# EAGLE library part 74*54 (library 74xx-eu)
4-wide AND OR INVERTER gates

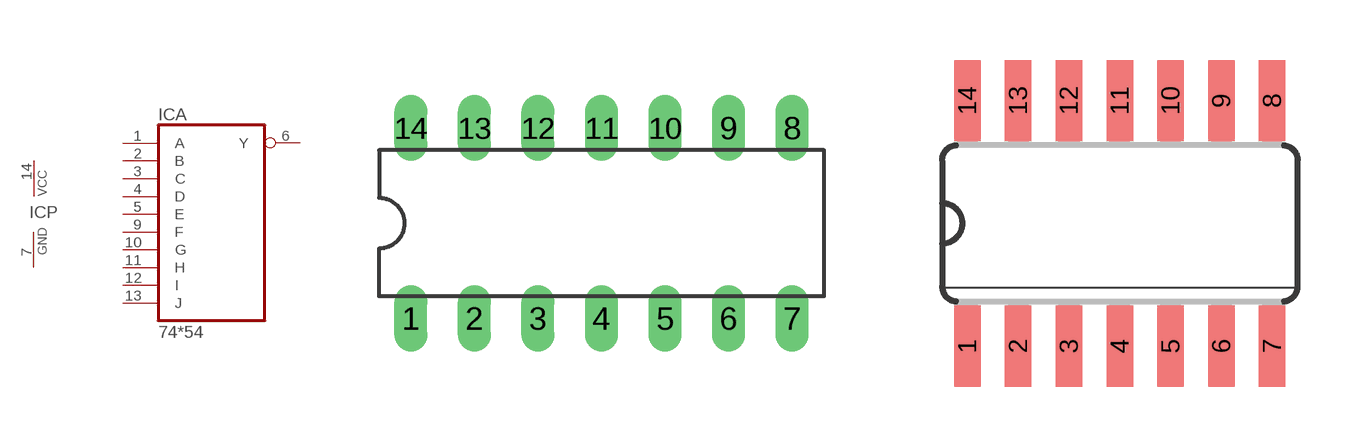
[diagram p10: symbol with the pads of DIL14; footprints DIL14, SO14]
Designator prefix IC; gates A=7454 P=PWRN

## 74LS54N  [DIL14]
1  A:A  in
2  A:B  in
3  A:C  in
4  A:D  in
5  A:E  in
6  A:Y  out
7  P:GND  pwr
9  A:F  in
10  A:G  in
11  A:H  in
12  A:I  in
13  A:J  in
14  P:VCC  pwr

## 74LS54D  [SO14]
Pads as for DIL14

## 74LS54FK  [LCC20]
2  A:A  in
3  A:B  in
4  A:C  in
6  A:D  in
8  A:E  in
9  A:Y  out
10  P:GND  pwr
13  A:F  in
14  A:G  in
16  A:H  in
18  A:I  in
19  A:J  in
20  P:VCC  pwr

## Footprint DIL14 (pad centres in mm)
Dual In Line Package
drill 0.813 long: 1 -7.62,-3.81; 2 -5.08,-3.81; 3 -2.54,-3.81; 4 0,-3.81; 5 2.54,-3.81; 6 5.08,-3.81; 7 7.62,-3.81; 8 7.62,3.81; 9 5.08,3.81; 10 2.54,3.81; 11 0,3.81; 12 -2.54,3.81; 13 -5.08,3.81; 14 -7.62,3.81

## Footprint SO14 (pad centres in mm)
Small Outline package 150 mil
smd 0.66 x 2.032: 1 -3.81,-3.073; 2 -2.54,-3.073; 3 -1.27,-3.073; 4 0,-3.073; 5 1.27,-3.073; 6 2.54,-3.073; 7 3.81,-3.073; 8 3.81,3.073; 9 2.54,3.073; 10 1.27,3.073; 11 0,3.073; 12 -1.27,3.073; 13 -2.54,3.073; 14 -3.81,3.073

## Footprint LCC20 (pad centres in mm)
Leadless Chip Carrier Ceramic Package
smd 0.8 x 3.4: 1 0,3.8
smd 0.8 x 2: 2 -1.27,4.5; 3 -2.54,4.5; 9 -2.54,-4.5; 10 -1.27,-4.5; 11 0,-4.5; 12 1.27,-4.5; 13 2.54,-4.5; 19 2.54,4.5; 20 1.27,4.5
smd 2 x 0.8: 4 -4.5,2.54; 5 -4.5,1.27; 6 -4.5,0; 7 -4.5,-1.27; 8 -4.5,-2.54; 14 4.5,-2.54; 15 4.5,-1.27; 16 4.5,0; 17 4.5,1.27; 18 4.5,2.54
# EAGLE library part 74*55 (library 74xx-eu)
2-wide 4-input AND OR INVERTER gate

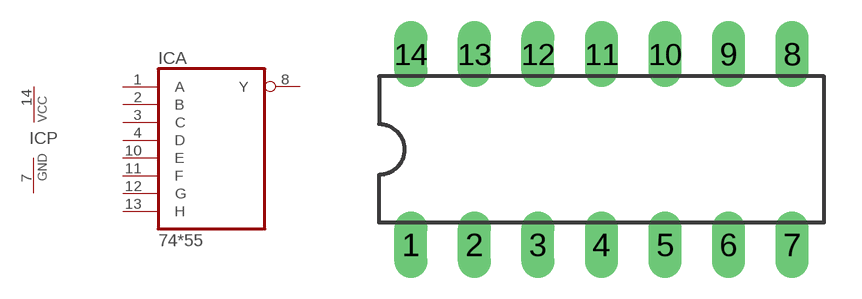
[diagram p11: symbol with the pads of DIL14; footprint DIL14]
Designator prefix IC; gates A=7455 P=PWRN

## 74LS55N  [DIL14]
1  A:A  in
2  A:B  in
3  A:C  in
4  A:D  in
7  P:GND  pwr
8  A:Y  out
10  A:E  in
11  A:F  in
12  A:G  in
13  A:H  in
14  P:VCC  pwr

## Footprint DIL14 (pad centres in mm)
Dual In Line Package
drill 0.813 long: 1 -7.62,-3.81; 2 -5.08,-3.81; 3 -2.54,-3.81; 4 0,-3.81; 5 2.54,-3.81; 6 5.08,-3.81; 7 7.62,-3.81; 8 7.62,3.81; 9 5.08,3.81; 10 2.54,3.81; 11 0,3.81; 12 -2.54,3.81; 13 -5.08,3.81; 14 -7.62,3.81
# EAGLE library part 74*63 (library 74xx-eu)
Hex current sensing INTERFACE gate, totem pole

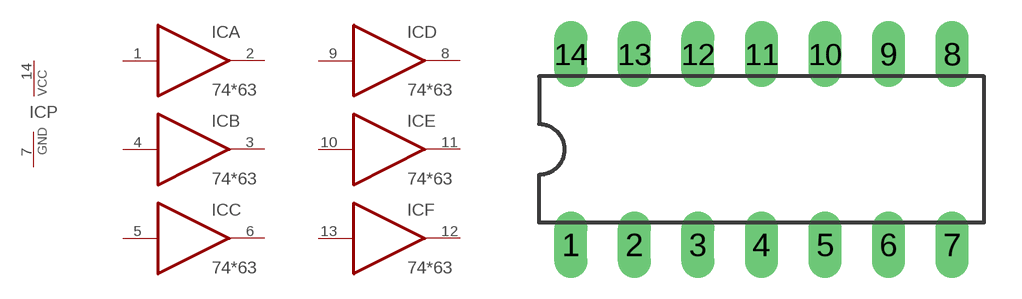
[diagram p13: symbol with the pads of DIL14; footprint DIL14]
Designator prefix IC; gates A=7463 B=7463 C=7463 D=7463 E=7463 F=7463 P=PWRN

## 74LS63N  [DIL14]
1  A:I  in
2  A:O  out
3  B:O  out
4  B:I  in
5  C:I  in
6  C:O  out
7  P:GND  pwr
8  D:O  out
9  D:I  in
10  E:I  in
11  E:O  out
12  F:O  out
13  F:I  in
14  P:VCC  pwr

## Footprint DIL14 (pad centres in mm)
Dual In Line Package
drill 0.813 long: 1 -7.62,-3.81; 2 -5.08,-3.81; 3 -2.54,-3.81; 4 0,-3.81; 5 2.54,-3.81; 6 5.08,-3.81; 7 7.62,-3.81; 8 7.62,3.81; 9 5.08,3.81; 10 2.54,3.81; 11 0,3.81; 12 -2.54,3.81; 13 -5.08,3.81; 14 -7.62,3.81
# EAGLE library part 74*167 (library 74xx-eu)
Synchronous decade rate MULTIPLIER

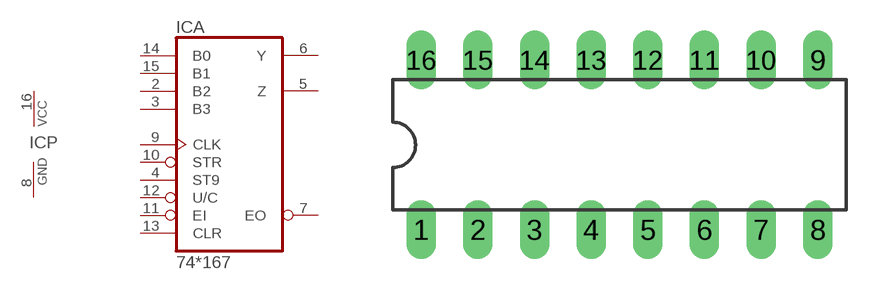
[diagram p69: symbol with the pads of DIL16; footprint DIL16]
Designator prefix IC; gates A=74167 P=PWRN

## 74167N  [DIL16]
2  A:B2  in
3  A:B3  in
4  A:ST9  in
5  A:Z  out
6  A:Y  out
7  A:EO  out
8  P:GND  pwr
9  A:CLK  in
10  A:STR  in
11  A:EI  in
12  A:U/C  in
13  A:CLR  in
14  A:B0  in
15  A:B1  in
16  P:VCC  pwr

## Footprint DIL16 (pad centres in mm)
Dual In Line Package
drill 0.813 long: 1 -8.89,-3.81; 2 -6.35,-3.81; 3 -3.81,-3.81; 4 -1.27,-3.81; 5 1.27,-3.81; 6 3.81,-3.81; 7 6.35,-3.81; 8 8.89,-3.81; 9 8.89,3.81; 10 6.35,3.81; 11 3.81,3.81; 12 1.27,3.81; 13 -1.27,3.81; 14 -3.81,3.81; 15 -6.35,3.81; 16 -8.89,3.81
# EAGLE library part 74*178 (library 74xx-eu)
4-bit parallel access SHIFT REGISTER

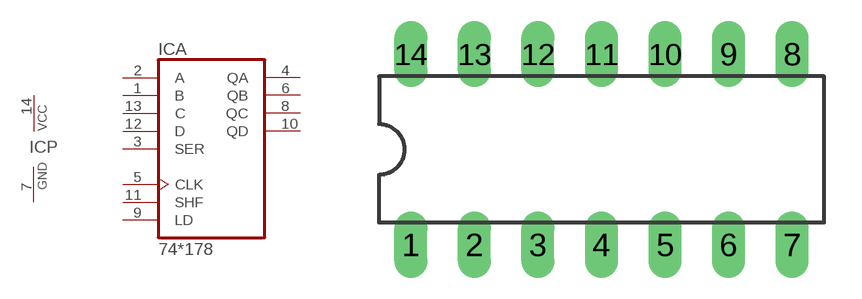
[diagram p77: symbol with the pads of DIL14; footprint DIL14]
Designator prefix IC; gates A=74178 P=PWRN

## 74178N  [DIL14]
1  A:B  in
2  A:A  in
3  A:SER  in
4  A:QA  out
5  A:CLK  in
6  A:QB  out
7  P:GND  pwr
8  A:QC  out
9  A:LD  in
10  A:QD  out
11  A:SHF  in
12  A:D  in
13  A:C  in
14  P:VCC  pwr

## Footprint DIL14 (pad centres in mm)
Dual In Line Package
drill 0.813 long: 1 -7.62,-3.81; 2 -5.08,-3.81; 3 -2.54,-3.81; 4 0,-3.81; 5 2.54,-3.81; 6 5.08,-3.81; 7 7.62,-3.81; 8 7.62,3.81; 9 5.08,3.81; 10 2.54,3.81; 11 0,3.81; 12 -2.54,3.81; 13 -5.08,3.81; 14 -7.62,3.81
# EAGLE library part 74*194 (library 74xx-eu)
4-bit bidirectional SHIFT REGISTER

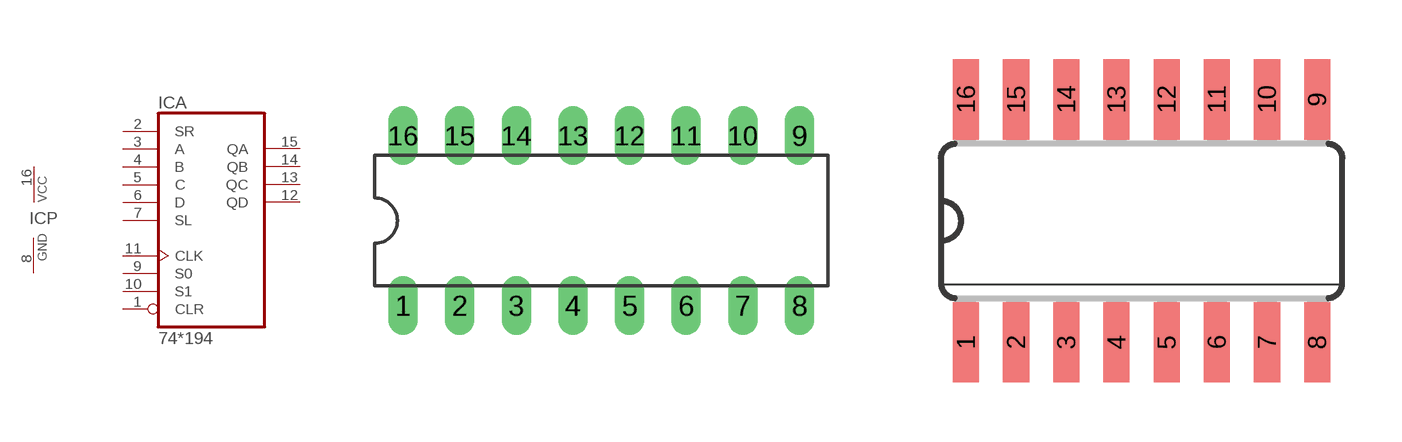
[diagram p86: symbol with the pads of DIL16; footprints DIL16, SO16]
Designator prefix IC; gates A=74194 P=PWRN

## 74AC194N, 74ACT194N, 74HC194N, 74HCT194N, 74LS194N, 74S194N  [DIL16]
1  A:CLR  in
2  A:SR  in
3  A:A  in
4  A:B  in
5  A:C  in
6  A:D  in
7  A:SL  in
8  P:GND  pwr
9  A:S0  in
10  A:S1  in
11  A:CLK  in
12  A:QD  out
13  A:QC  out
14  A:QB  out
15  A:QA  out
16  P:VCC  pwr

## 74AC194D, 74ACT194D, 74HC194D, 74HCT194D, 74LS194D, 74S194D  [SO16]
Pads as for DIL16

## 74AC194FK, 74ACT194FK, 74HC194FK, 74HCT194FK, 74LS194FK, 74S194FK  [LCC20]
2  A:CLR  in
3  A:SR  in
4  A:A  in
5  A:B  in
7  A:C  in
8  A:D  in
9  A:SL  in
10  P:GND  pwr
12  A:S0  in
13  A:S1  in
14  A:CLK  in
15  A:QD  out
17  A:QC  out
18  A:QB  out
19  A:QA  out
20  P:VCC  pwr

## Footprint DIL16 (pad centres in mm)
Dual In Line Package
drill 0.813 long: 1 -8.89,-3.81; 2 -6.35,-3.81; 3 -3.81,-3.81; 4 -1.27,-3.81; 5 1.27,-3.81; 6 3.81,-3.81; 7 6.35,-3.81; 8 8.89,-3.81; 9 8.89,3.81; 10 6.35,3.81; 11 3.81,3.81; 12 1.27,3.81; 13 -1.27,3.81; 14 -3.81,3.81; 15 -6.35,3.81; 16 -8.89,3.81

## Footprint SO16 (pad centres in mm)
Small Outline package 150 mil
smd 0.66 x 2.032: 1 -4.445,-3.073; 2 -3.175,-3.073; 3 -1.905,-3.073; 4 -0.635,-3.073; 5 0.635,-3.073; 6 1.905,-3.073; 7 3.175,-3.073; 8 4.445,-3.073; 9 4.445,3.073; 10 3.175,3.073; 11 1.905,3.073; 12 0.635,3.073; 13 -0.635,3.073; 14 -1.905,3.073; 15 -3.175,3.073; 16 -4.445,3.073

## Footprint LCC20 (pad centres in mm)
Leadless Chip Carrier Ceramic Package
smd 0.8 x 3.4: 1 0,3.8
smd 0.8 x 2: 2 -1.27,4.5; 3 -2.54,4.5; 9 -2.54,-4.5; 10 -1.27,-4.5; 11 0,-4.5; 12 1.27,-4.5; 13 2.54,-4.5; 19 2.54,4.5; 20 1.27,4.5
smd 2 x 0.8: 4 -4.5,2.54; 5 -4.5,1.27; 6 -4.5,0; 7 -4.5,-1.27; 8 -4.5,-2.54; 14 4.5,-2.54; 15 4.5,-1.27; 16 4.5,0; 17 4.5,1.27; 18 4.5,2.54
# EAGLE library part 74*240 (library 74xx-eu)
Octal BUFFER and LINE DRIVER, 3-state

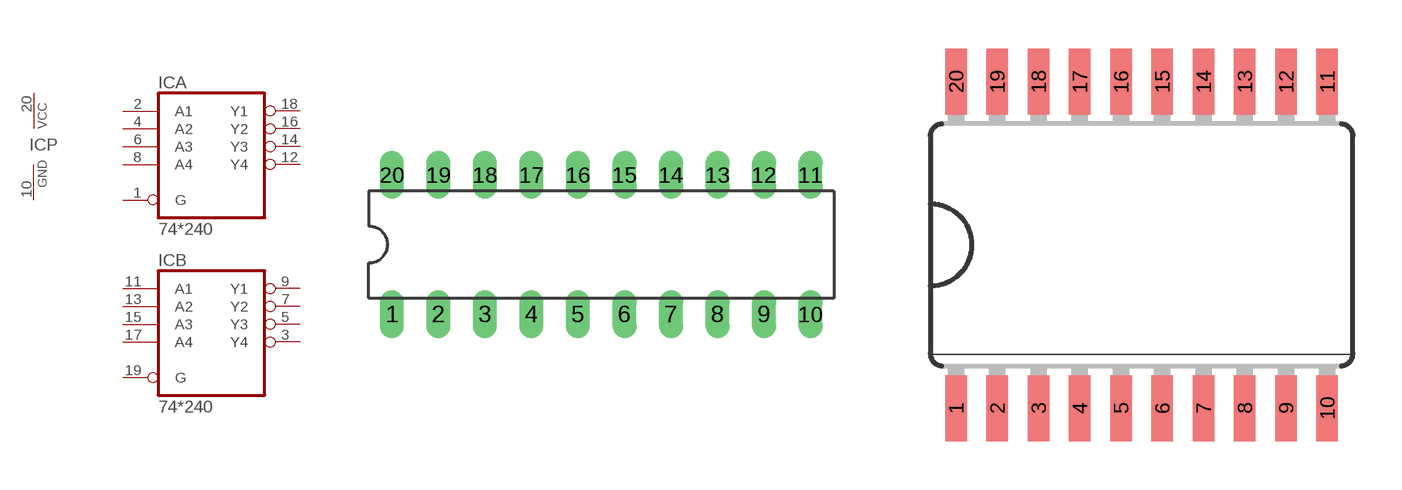
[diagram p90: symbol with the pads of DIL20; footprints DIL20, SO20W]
Designator prefix IC; gates A=74240 B=74240 P=PWRN

## 74AC240N, 74ACT240N, 74HC240N, 74HCT240N, 74LS240N, 74S240N  [DIL20]
1  A:G  in
2  A:A1  in
3  B:Y4  hiz
4  A:A2  in
5  B:Y3  hiz
6  A:A3  in
7  B:Y2  hiz
8  A:A4  in
9  B:Y1  hiz
10  P:GND  pwr
11  B:A1  in
12  A:Y4  hiz
13  B:A2  in
14  A:Y3  hiz
15  B:A3  in
16  A:Y2  hiz
17  B:A4  in
18  A:Y1  hiz
19  B:G  in
20  P:VCC  pwr

## 74AC240DW, 74ACT240DW, 74HC240DW, 74HCT240DW, 74LS240DW, 74S240DW  [SO20W]
Pads as for DIL20

## 74AC240FK, 74ACT240FK, 74HC240FK, 74HCT240FK, 74LS240FK, 74S240FK  [LCC20]
Pads as for DIL20

## Footprint DIL20 (pad centres in mm)
Dual In Line Package
drill 0.813 long: 1 -11.43,-3.81; 2 -8.89,-3.81; 3 -6.35,-3.81; 4 -3.81,-3.81; 5 -1.27,-3.81; 6 1.27,-3.81; 7 3.81,-3.81; 8 6.35,-3.81; 9 8.89,-3.81; 10 11.43,-3.81; 11 11.43,3.81; 12 8.89,3.81; 13 6.35,3.81; 14 3.81,3.81; 15 1.27,3.81; 16 -1.27,3.81; 17 -3.81,3.81; 18 -6.35,3.81; 19 -8.89,3.81; 20 -11.43,3.81

## Footprint SO20W (pad centres in mm)
Wide Small Outline package 300 mil
smd 0.66 x 2.032: 1 -5.715,-5.029; 2 -4.445,-5.029; 3 -3.175,-5.029; 4 -1.905,-5.029; 5 -0.635,-5.029; 6 0.635,-5.029; 7 1.905,-5.029; 8 3.175,-5.029; 9 4.445,-5.029; 10 5.715,-5.029; 11 5.715,5.029; 12 4.445,5.029; 13 3.175,5.029; 14 1.905,5.029; 15 0.635,5.029; 16 -0.635,5.029; 17 -1.905,5.029; 18 -3.175,5.029; 19 -4.445,5.029; 20 -5.715,5.029

## Footprint LCC20 (pad centres in mm)
Leadless Chip Carrier Ceramic Package
smd 0.8 x 3.4: 1 0,3.8
smd 0.8 x 2: 2 -1.27,4.5; 3 -2.54,4.5; 9 -2.54,-4.5; 10 -1.27,-4.5; 11 0,-4.5; 12 1.27,-4.5; 13 2.54,-4.5; 19 2.54,4.5; 20 1.27,4.5
smd 2 x 0.8: 4 -4.5,2.54; 5 -4.5,1.27; 6 -4.5,0; 7 -4.5,-1.27; 8 -4.5,-2.54; 14 4.5,-2.54; 15 4.5,-1.27; 16 4.5,0; 17 4.5,1.27; 18 4.5,2.54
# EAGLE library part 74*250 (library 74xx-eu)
1 of 16 data GENERATOR/MULTIPLEXER, 3-state

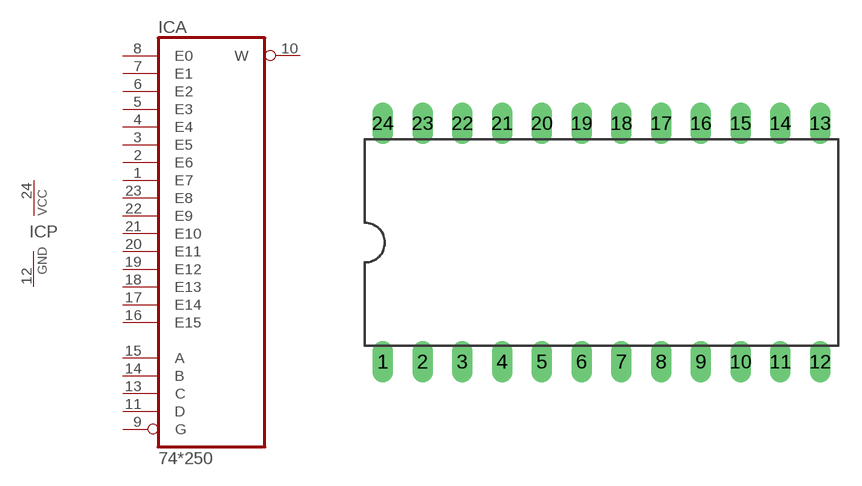
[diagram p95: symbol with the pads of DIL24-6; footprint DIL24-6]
Designator prefix IC; gates A=74250 P=PWRN

## 74250N  [DIL24-6]
1  A:E7  in
2  A:E6  in
3  A:E5  in
4  A:E4  in
5  A:E3  in
6  A:E2  in
7  A:E1  in
8  A:E0  in
9  A:G  in
10  A:W  hiz
11  A:D  in
12  P:GND  pwr
13  A:C  in
14  A:B  in
15  A:A  in
16  A:E15  in
17  A:E14  in
18  A:E13  in
19  A:E12  in
20  A:E11  in
21  A:E10  in
22  A:E9  in
23  A:E8  in
24  P:VCC  pwr

## Footprint DIL24-6 (pad centres in mm)
Dual In Line Package 0.6 inch
drill 0.813 long: 1 -13.97,-7.62; 2 -11.43,-7.62; 3 -8.89,-7.62; 4 -6.35,-7.62; 5 -3.81,-7.62; 6 -1.27,-7.62; 7 1.27,-7.62; 8 3.81,-7.62; 9 6.35,-7.62; 10 8.89,-7.62; 11 11.43,-7.62; 12 13.97,-7.62; 13 13.97,7.62; 14 11.43,7.62; 15 8.89,7.62; 16 6.35,7.62; 17 3.81,7.62; 18 1.27,7.62; 19 -1.27,7.62; 20 -3.81,7.62; 21 -6.35,7.62; 22 -8.89,7.62; 23 -11.43,7.62; 24 -13.97,7.62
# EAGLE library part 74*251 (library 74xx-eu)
1 of 8 data SELECTOR/MULTIPLEXER, 3-state

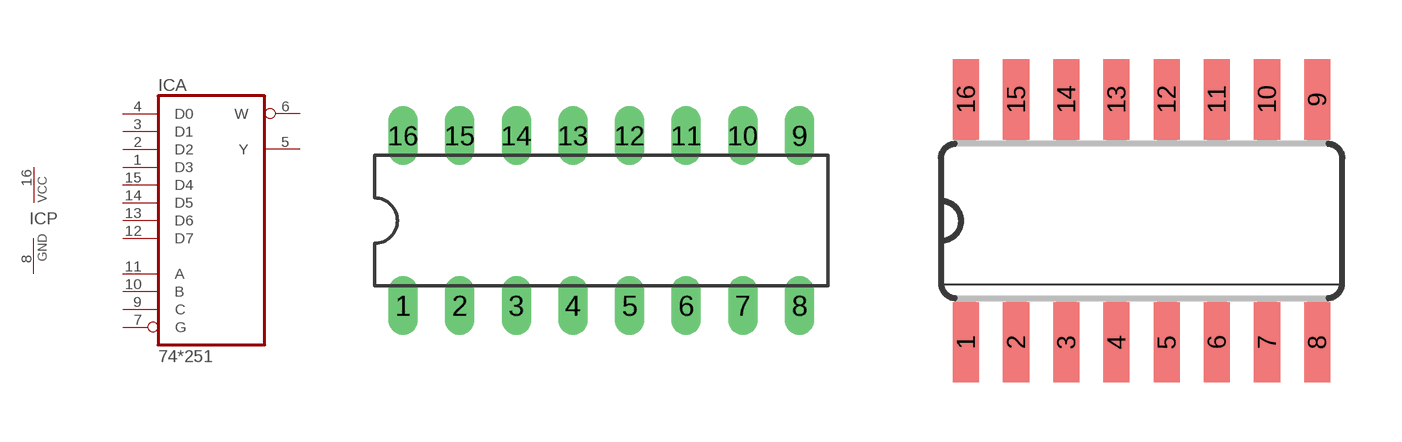
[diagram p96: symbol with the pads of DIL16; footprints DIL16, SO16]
Designator prefix IC; gates A=74251 P=PWRN

## 74AC251N, 74ACT251N, 74HC251N, 74HCT251N, 74LS251N, 74S251N  [DIL16]
1  A:D3  in
2  A:D2  in
3  A:D1  in
4  A:D0  in
5  A:Y  hiz
6  A:W  hiz
7  A:G  in
8  P:GND  pwr
9  A:C  in
10  A:B  in
11  A:A  in
12  A:D7  in
13  A:D6  in
14  A:D5  in
15  A:D4  in
16  P:VCC  pwr

## 74AC251D, 74ACT251D, 74HC251D, 74HCT251D, 74LS251D, 74S251D  [SO16]
Pads as for DIL16

## 74AC251FK, 74ACT251FK, 74HC251FK, 74HCT251FK, 74LS251FK, 74S251FK  [LCC20]
2  A:D3  in
3  A:D2  in
4  A:D1  in
5  A:D0  in
7  A:Y  hiz
8  A:W  hiz
9  A:G  in
10  P:GND  pwr
12  A:C  in
13  A:B  in
14  A:A  in
15  A:D7  in
17  A:D6  in
18  A:D5  in
19  A:D4  in
20  P:VCC  pwr

## Footprint DIL16 (pad centres in mm)
Dual In Line Package
drill 0.813 long: 1 -8.89,-3.81; 2 -6.35,-3.81; 3 -3.81,-3.81; 4 -1.27,-3.81; 5 1.27,-3.81; 6 3.81,-3.81; 7 6.35,-3.81; 8 8.89,-3.81; 9 8.89,3.81; 10 6.35,3.81; 11 3.81,3.81; 12 1.27,3.81; 13 -1.27,3.81; 14 -3.81,3.81; 15 -6.35,3.81; 16 -8.89,3.81

## Footprint SO16 (pad centres in mm)
Small Outline package 150 mil
smd 0.66 x 2.032: 1 -4.445,-3.073; 2 -3.175,-3.073; 3 -1.905,-3.073; 4 -0.635,-3.073; 5 0.635,-3.073; 6 1.905,-3.073; 7 3.175,-3.073; 8 4.445,-3.073; 9 4.445,3.073; 10 3.175,3.073; 11 1.905,3.073; 12 0.635,3.073; 13 -0.635,3.073; 14 -1.905,3.073; 15 -3.175,3.073; 16 -4.445,3.073

## Footprint LCC20 (pad centres in mm)
Leadless Chip Carrier Ceramic Package
smd 0.8 x 3.4: 1 0,3.8
smd 0.8 x 2: 2 -1.27,4.5; 3 -2.54,4.5; 9 -2.54,-4.5; 10 -1.27,-4.5; 11 0,-4.5; 12 1.27,-4.5; 13 2.54,-4.5; 19 2.54,4.5; 20 1.27,4.5
smd 2 x 0.8: 4 -4.5,2.54; 5 -4.5,1.27; 6 -4.5,0; 7 -4.5,-1.27; 8 -4.5,-2.54; 14 4.5,-2.54; 15 4.5,-1.27; 16 4.5,0; 17 4.5,1.27; 18 4.5,2.54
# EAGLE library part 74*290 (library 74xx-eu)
Decade and 4-bit BINARY COUNTER

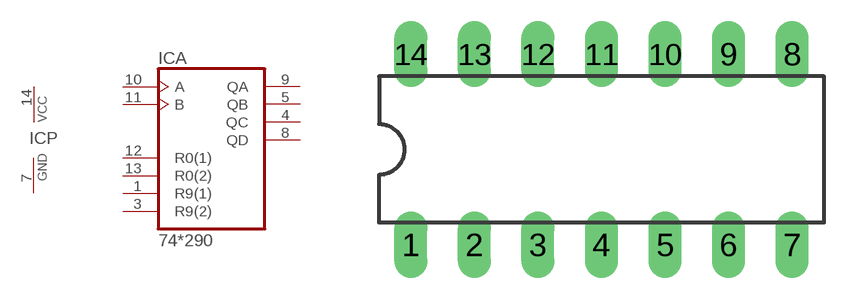
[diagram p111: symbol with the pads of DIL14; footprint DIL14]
Designator prefix IC; gates A=74290 P=PWRN

## 74290N  [DIL14]
1  A:R9(1)  in
3  A:R9(2)  in
4  A:QC  out
5  A:QB  out
7  P:GND  pwr
8  A:QD  out
9  A:QA  out
10  A:A  in
11  A:B  in
12  A:R0(1)  in
13  A:R0(2)  in
14  P:VCC  pwr

## Footprint DIL14 (pad centres in mm)
Dual In Line Package
drill 0.813 long: 1 -7.62,-3.81; 2 -5.08,-3.81; 3 -2.54,-3.81; 4 0,-3.81; 5 2.54,-3.81; 6 5.08,-3.81; 7 7.62,-3.81; 8 7.62,3.81; 9 5.08,3.81; 10 2.54,3.81; 11 0,3.81; 12 -2.54,3.81; 13 -5.08,3.81; 14 -7.62,3.81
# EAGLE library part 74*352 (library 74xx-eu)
Dual 4-to 1 line data SELECTOR/MULTIPLEXER

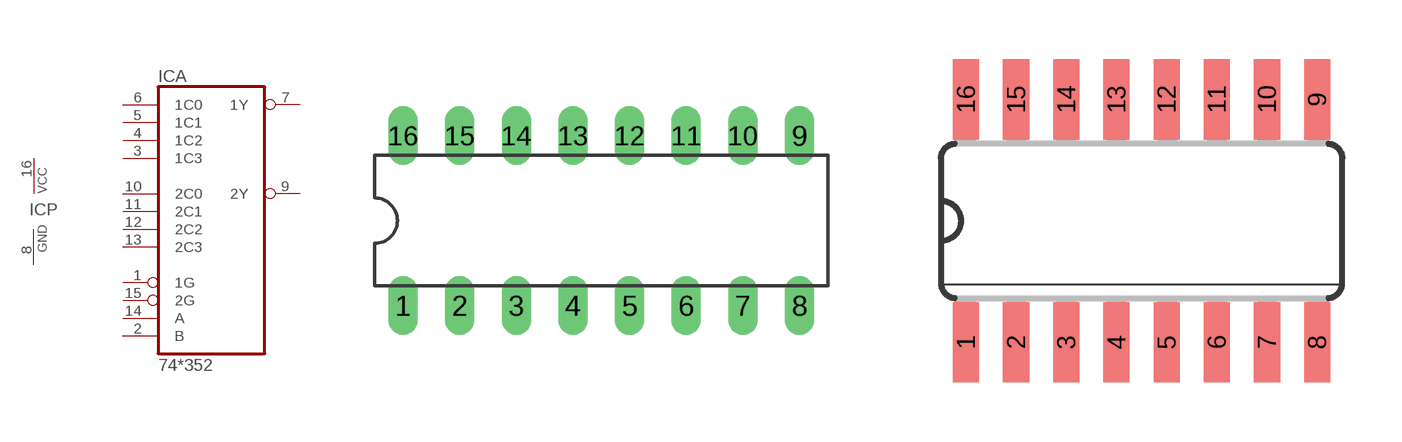
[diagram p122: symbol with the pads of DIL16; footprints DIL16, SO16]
Designator prefix IC; gates A=74352 P=PWRN

## 74AC352N, 74ACT352N, 74HC352N, 74LS352N  [DIL16]
1  A:1G  in
2  A:B  in
3  A:1C3  in
4  A:1C2  in
5  A:1C1  in
6  A:1C0  in
7  A:1Y  out
8  P:GND  pwr
9  A:2Y  out
10  A:2C0  in
11  A:2C1  in
12  A:2C2  in
13  A:2C3  in
14  A:A  in
15  A:2G  in
16  P:VCC  pwr

## 74AC352D, 74ACT352D, 74HC352D, 74LS352D  [SO16]
Pads as for DIL16

## Footprint DIL16 (pad centres in mm)
Dual In Line Package
drill 0.813 long: 1 -8.89,-3.81; 2 -6.35,-3.81; 3 -3.81,-3.81; 4 -1.27,-3.81; 5 1.27,-3.81; 6 3.81,-3.81; 7 6.35,-3.81; 8 8.89,-3.81; 9 8.89,3.81; 10 6.35,3.81; 11 3.81,3.81; 12 1.27,3.81; 13 -1.27,3.81; 14 -3.81,3.81; 15 -6.35,3.81; 16 -8.89,3.81

## Footprint SO16 (pad centres in mm)
Small Outline package 150 mil
smd 0.66 x 2.032: 1 -4.445,-3.073; 2 -3.175,-3.073; 3 -1.905,-3.073; 4 -0.635,-3.073; 5 0.635,-3.073; 6 1.905,-3.073; 7 3.175,-3.073; 8 4.445,-3.073; 9 4.445,3.073; 10 3.175,3.073; 11 1.905,3.073; 12 0.635,3.073; 13 -0.635,3.073; 14 -1.905,3.073; 15 -3.175,3.073; 16 -4.445,3.073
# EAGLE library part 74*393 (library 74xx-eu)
Dual 4-bit decade and binary COUNTER

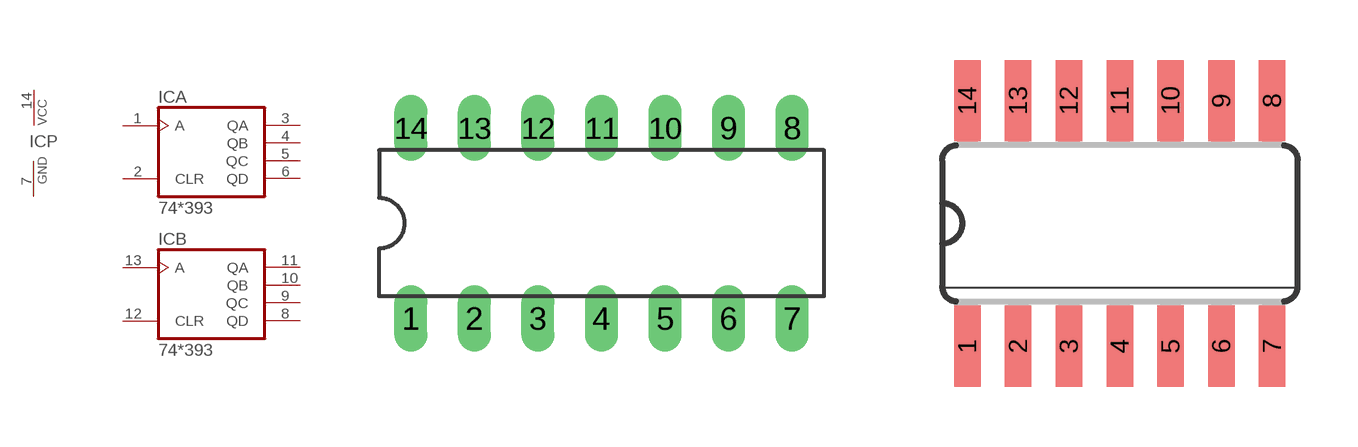
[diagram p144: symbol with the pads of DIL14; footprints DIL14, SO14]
Designator prefix IC; gates A=74393 B=74393 P=PWRN

## 74393N, 74AC393N, 74HC393N, 74HCT393N, 74LS393N  [DIL14]
1  A:A  in
2  A:CLR  in
3  A:QA  out
4  A:QB  out
5  A:QC  out
6  A:QD  out
7  P:GND  pwr
8  B:QD  out
9  B:QC  out
10  B:QB  out
11  B:QA  out
12  B:CLR  in
13  B:A  in
14  P:VCC  pwr

## 74AC393D, 74HC393D, 74HCT393D  [SO14]
Pads as for DIL14

## 74AC393FK, 74HC393FK, 74HCT393FK  [LCC20]
2  A:A  in
3  A:CLR  in
4  A:QA  out
6  A:QB  out
8  A:QC  out
9  A:QD  out
10  P:GND  pwr
12  B:QD  out
13  B:QC  out
14  B:QB  out
16  B:QA  out
18  B:CLR  in
19  B:A  in
20  P:VCC  pwr

## Footprint DIL14 (pad centres in mm)
Dual In Line Package
drill 0.813 long: 1 -7.62,-3.81; 2 -5.08,-3.81; 3 -2.54,-3.81; 4 0,-3.81; 5 2.54,-3.81; 6 5.08,-3.81; 7 7.62,-3.81; 8 7.62,3.81; 9 5.08,3.81; 10 2.54,3.81; 11 0,3.81; 12 -2.54,3.81; 13 -5.08,3.81; 14 -7.62,3.81

## Footprint SO14 (pad centres in mm)
Small Outline package 150 mil
smd 0.66 x 2.032: 1 -3.81,-3.073; 2 -2.54,-3.073; 3 -1.27,-3.073; 4 0,-3.073; 5 1.27,-3.073; 6 2.54,-3.073; 7 3.81,-3.073; 8 3.81,3.073; 9 2.54,3.073; 10 1.27,3.073; 11 0,3.073; 12 -1.27,3.073; 13 -2.54,3.073; 14 -3.81,3.073

## Footprint LCC20 (pad centres in mm)
Leadless Chip Carrier Ceramic Package
smd 0.8 x 3.4: 1 0,3.8
smd 0.8 x 2: 2 -1.27,4.5; 3 -2.54,4.5; 9 -2.54,-4.5; 10 -1.27,-4.5; 11 0,-4.5; 12 1.27,-4.5; 13 2.54,-4.5; 19 2.54,4.5; 20 1.27,4.5
smd 2 x 0.8: 4 -4.5,2.54; 5 -4.5,1.27; 6 -4.5,0; 7 -4.5,-1.27; 8 -4.5,-2.54; 14 4.5,-2.54; 15 4.5,-1.27; 16 4.5,0; 17 4.5,1.27; 18 4.5,2.54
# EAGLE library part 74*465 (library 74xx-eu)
Octal BUFFER, 3-state

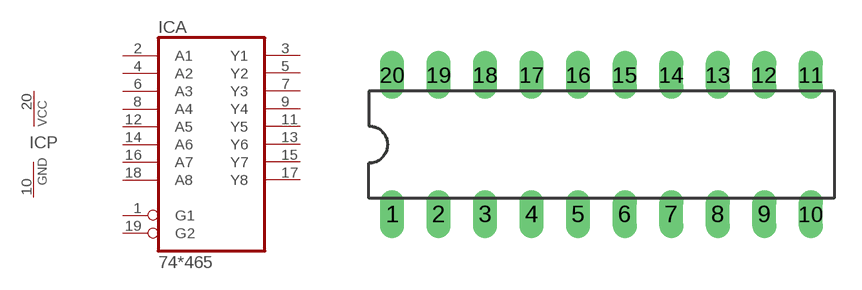
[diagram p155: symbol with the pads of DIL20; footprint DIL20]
Designator prefix IC; gates A=74465 P=PWRN

## 74465N  [DIL20]
1  A:G1  in
2  A:A1  in
3  A:Y1  hiz
4  A:A2  in
5  A:Y2  hiz
6  A:A3  in
7  A:Y3  hiz
8  A:A4  in
9  A:Y4  hiz
10  P:GND  pwr
11  A:Y5  hiz
12  A:A5  in
13  A:Y6  hiz
14  A:A6  in
15  A:Y7  hiz
16  A:A7  in
17  A:Y8  hiz
18  A:A8  in
19  A:G2  in
20  P:VCC  pwr

## Footprint DIL20 (pad centres in mm)
Dual In Line Package
drill 0.813 long: 1 -11.43,-3.81; 2 -8.89,-3.81; 3 -6.35,-3.81; 4 -3.81,-3.81; 5 -1.27,-3.81; 6 1.27,-3.81; 7 3.81,-3.81; 8 6.35,-3.81; 9 8.89,-3.81; 10 11.43,-3.81; 11 11.43,3.81; 12 8.89,3.81; 13 6.35,3.81; 14 3.81,3.81; 15 1.27,3.81; 16 -1.27,3.81; 17 -3.81,3.81; 18 -6.35,3.81; 19 -8.89,3.81; 20 -11.43,3.81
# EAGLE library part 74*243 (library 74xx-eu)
Quadruple BUS TRANSCEIVER

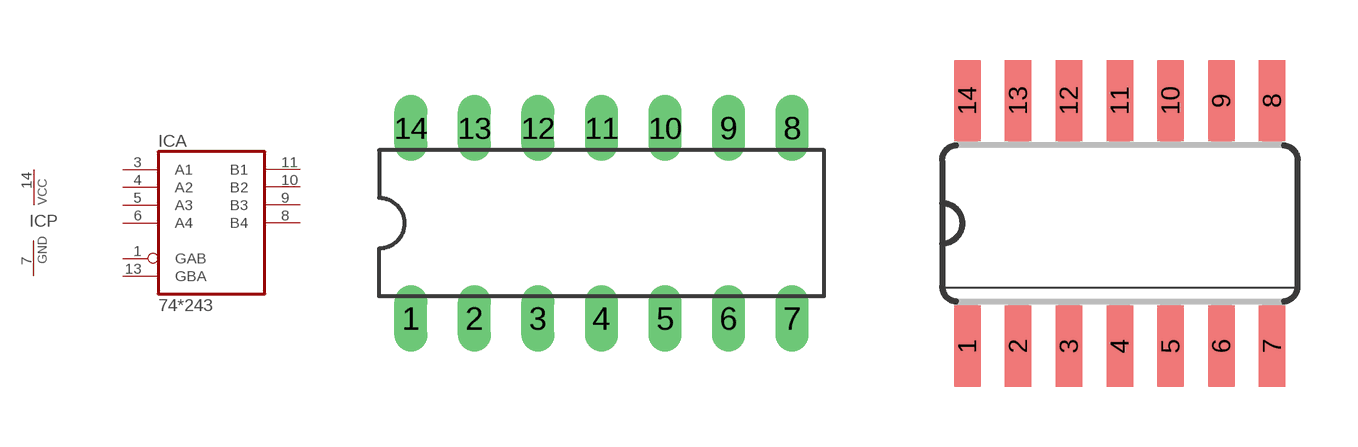
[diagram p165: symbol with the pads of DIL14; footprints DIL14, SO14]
Designator prefix IC; gates A=74243 P=PWRN

## 74HC243N, 74HCT243N, 74LS243N  [DIL14]
1  A:GAB  in
3  A:A1
4  A:A2
5  A:A3
6  A:A4
7  P:GND  pwr
8  A:B4
9  A:B3
10  A:B2
11  A:B1
13  A:GBA  in
14  P:VCC  pwr

## 74HC243D, 74HCT243D, 74LS243D  [SO14]
Pads as for DIL14

## 74HC243FK, 74HCT243FK, 74LS243FK  [LCC20]
2  A:GAB  in
4  A:A1
6  A:A2
8  A:A3
9  A:A4
10  P:GND  pwr
12  A:B4
13  A:B3
14  A:B2
16  A:B1
19  A:GBA  in
20  P:VCC  pwr

## Footprint DIL14 (pad centres in mm)
Dual In Line Package
drill 0.813 long: 1 -7.62,-3.81; 2 -5.08,-3.81; 3 -2.54,-3.81; 4 0,-3.81; 5 2.54,-3.81; 6 5.08,-3.81; 7 7.62,-3.81; 8 7.62,3.81; 9 5.08,3.81; 10 2.54,3.81; 11 0,3.81; 12 -2.54,3.81; 13 -5.08,3.81; 14 -7.62,3.81

## Footprint SO14 (pad centres in mm)
Small Outline package 150 mil
smd 0.66 x 2.032: 1 -3.81,-3.073; 2 -2.54,-3.073; 3 -1.27,-3.073; 4 0,-3.073; 5 1.27,-3.073; 6 2.54,-3.073; 7 3.81,-3.073; 8 3.81,3.073; 9 2.54,3.073; 10 1.27,3.073; 11 0,3.073; 12 -1.27,3.073; 13 -2.54,3.073; 14 -3.81,3.073

## Footprint LCC20 (pad centres in mm)
Leadless Chip Carrier Ceramic Package
smd 0.8 x 3.4: 1 0,3.8
smd 0.8 x 2: 2 -1.27,4.5; 3 -2.54,4.5; 9 -2.54,-4.5; 10 -1.27,-4.5; 11 0,-4.5; 12 1.27,-4.5; 13 2.54,-4.5; 19 2.54,4.5; 20 1.27,4.5
smd 2 x 0.8: 4 -4.5,2.54; 5 -4.5,1.27; 6 -4.5,0; 7 -4.5,-1.27; 8 -4.5,-2.54; 14 4.5,-2.54; 15 4.5,-1.27; 16 4.5,0; 17 4.5,1.27; 18 4.5,2.54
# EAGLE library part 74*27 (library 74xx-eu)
Triple 3-input NOR gate

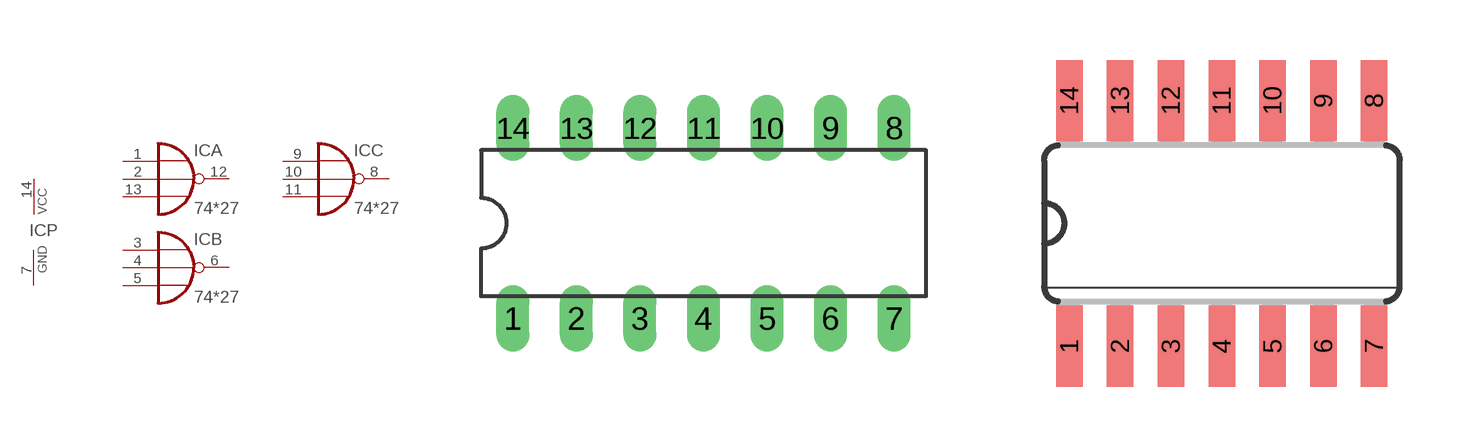
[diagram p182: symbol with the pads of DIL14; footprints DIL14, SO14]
Designator prefix IC; gates A=7427 B=7427 C=7427 P=PWRN

## 74AC27N, 74ACT27N, 74ALS27N, 74AS27N, 74HC27N, 74HCT27N, 74LS27N  [DIL14]
1  A:I0  in
2  A:I1  in
3  B:I0  in
4  B:I1  in
5  B:I2  in
6  B:O  out
7  P:GND  pwr
8  C:O  out
9  C:I0  in
10  C:I1  in
11  C:I2  in
12  A:O  out
13  A:I2  in
14  P:VCC  pwr

## 74AC27D, 74ACT27D, 74ALS27D, 74AS27D, 74HC27D, 74HCT27D, 74LS27D  [SO14]
Pads as for DIL14

## 74AC27FK, 74ACT27FK, 74ALS27FK, 74AS27FK, 74HC27FK, 74HCT27FK, 74LS27FK  [LCC20]
2  A:I0  in
3  A:I1  in
4  B:I0  in
6  B:I1  in
8  B:I2  in
9  B:O  out
10  P:GND  pwr
12  C:O  out
13  C:I0  in
14  C:I1  in
16  C:I2  in
18  A:O  out
19  A:I2  in
20  P:VCC  pwr

## Footprint DIL14 (pad centres in mm)
Dual In Line Package
drill 0.813 long: 1 -7.62,-3.81; 2 -5.08,-3.81; 3 -2.54,-3.81; 4 0,-3.81; 5 2.54,-3.81; 6 5.08,-3.81; 7 7.62,-3.81; 8 7.62,3.81; 9 5.08,3.81; 10 2.54,3.81; 11 0,3.81; 12 -2.54,3.81; 13 -5.08,3.81; 14 -7.62,3.81

## Footprint SO14 (pad centres in mm)
Small Outline package 150 mil
smd 0.66 x 2.032: 1 -3.81,-3.073; 2 -2.54,-3.073; 3 -1.27,-3.073; 4 0,-3.073; 5 1.27,-3.073; 6 2.54,-3.073; 7 3.81,-3.073; 8 3.81,3.073; 9 2.54,3.073; 10 1.27,3.073; 11 0,3.073; 12 -1.27,3.073; 13 -2.54,3.073; 14 -3.81,3.073

## Footprint LCC20 (pad centres in mm)
Leadless Chip Carrier Ceramic Package
smd 0.8 x 3.4: 1 0,3.8
smd 0.8 x 2: 2 -1.27,4.5; 3 -2.54,4.5; 9 -2.54,-4.5; 10 -1.27,-4.5; 11 0,-4.5; 12 1.27,-4.5; 13 2.54,-4.5; 19 2.54,4.5; 20 1.27,4.5
smd 2 x 0.8: 4 -4.5,2.54; 5 -4.5,1.27; 6 -4.5,0; 7 -4.5,-1.27; 8 -4.5,-2.54; 14 4.5,-2.54; 15 4.5,-1.27; 16 4.5,0; 17 4.5,1.27; 18 4.5,2.54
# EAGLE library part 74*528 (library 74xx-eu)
12-bit programmable COMPARATOR

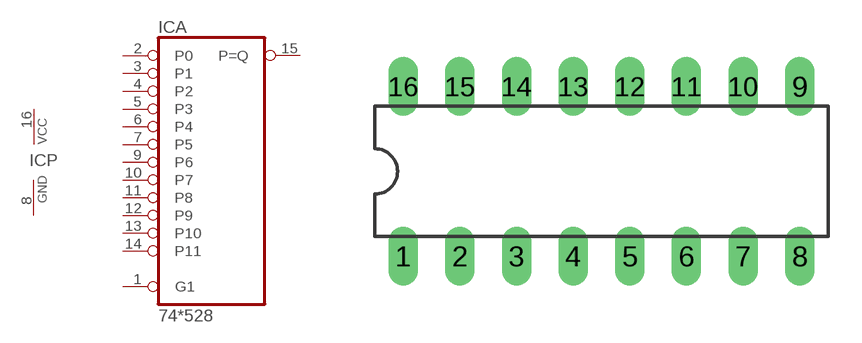
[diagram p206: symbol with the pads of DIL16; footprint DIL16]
Designator prefix IC; gates A=74528 P=PWRN

## 74ALS528N  [DIL16]
1  A:G1  in
2  A:P0  in
3  A:P1  in
4  A:P2  in
5  A:P3  in
6  A:P4  in
7  A:P5  in
8  P:GND  pwr
9  A:P6  in
10  A:P7  in
11  A:P8  in
12  A:P9  in
13  A:P10  in
14  A:P11  in
15  A:P=Q  out
16  P:VCC  pwr

## Footprint DIL16 (pad centres in mm)
Dual In Line Package
drill 0.813 long: 1 -8.89,-3.81; 2 -6.35,-3.81; 3 -3.81,-3.81; 4 -1.27,-3.81; 5 1.27,-3.81; 6 3.81,-3.81; 7 6.35,-3.81; 8 8.89,-3.81; 9 8.89,3.81; 10 6.35,3.81; 11 3.81,3.81; 12 1.27,3.81; 13 -1.27,3.81; 14 -3.81,3.81; 15 -6.35,3.81; 16 -8.89,3.81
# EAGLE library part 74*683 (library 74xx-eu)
8-bit MAGNITUDE/IDENTITY COMPARATOR, open collector

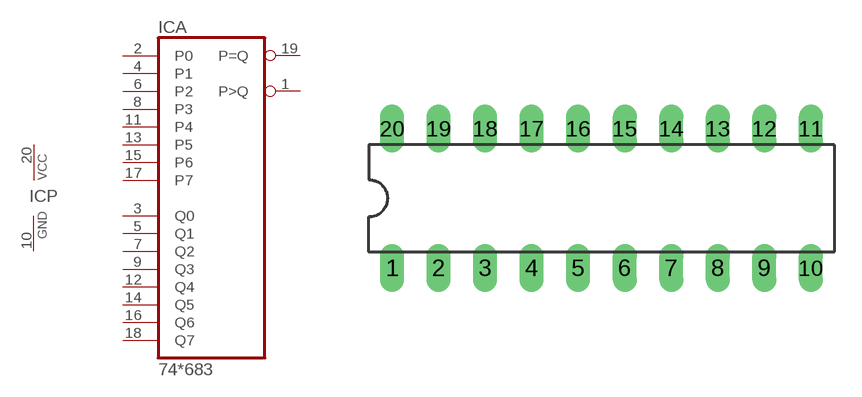
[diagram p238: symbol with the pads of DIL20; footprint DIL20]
Designator prefix IC; gates A=74683 P=PWRN

## 74683N  [DIL20]
1  A:P>Q  oc
2  A:P0  in
3  A:Q0  in
4  A:P1  in
5  A:Q1  in
6  A:P2  in
7  A:Q2  in
8  A:P3  in
9  A:Q3  in
10  P:GND  pwr
11  A:P4  in
12  A:Q4  in
13  A:P5  in
14  A:Q5  in
15  A:P6  in
16  A:Q6  in
17  A:P7  in
18  A:Q7  in
19  A:P=Q  oc
20  P:VCC  pwr

## Footprint DIL20 (pad centres in mm)
Dual In Line Package
drill 0.813 long: 1 -11.43,-3.81; 2 -8.89,-3.81; 3 -6.35,-3.81; 4 -3.81,-3.81; 5 -1.27,-3.81; 6 1.27,-3.81; 7 3.81,-3.81; 8 6.35,-3.81; 9 8.89,-3.81; 10 11.43,-3.81; 11 11.43,3.81; 12 8.89,3.81; 13 6.35,3.81; 14 3.81,3.81; 15 1.27,3.81; 16 -1.27,3.81; 17 -3.81,3.81; 18 -6.35,3.81; 19 -8.89,3.81; 20 -11.43,3.81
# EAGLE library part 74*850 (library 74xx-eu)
16-to 1 line MULTIPLEXER

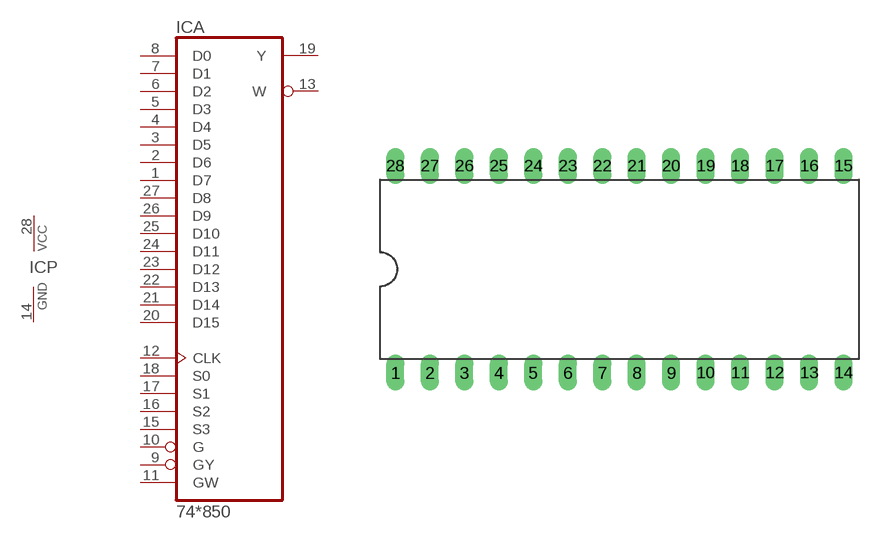
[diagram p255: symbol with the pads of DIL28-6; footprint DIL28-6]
Designator prefix IC; gates A=74850 P=PWRN

## 74AS850N  [DIL28-6]
1  A:D7  in
2  A:D6  in
3  A:D5  in
4  A:D4  in
5  A:D3  in
6  A:D2  in
7  A:D1  in
8  A:D0  in
9  A:GY  in
10  A:G  in
11  A:GW  in
12  A:CLK  in
13  A:W  hiz
14  P:GND  pwr
15  A:S3  in
16  A:S2  in
17  A:S1  in
18  A:S0  in
19  A:Y  hiz
20  A:D15  in
21  A:D14  in
22  A:D13  in
23  A:D12  in
24  A:D11  in
25  A:D10  in
26  A:D9  in
27  A:D8  in
28  P:VCC  pwr

## Footprint DIL28-6 (pad centres in mm)
Dual In Line Package 0.6 inch
drill 0.813 long: 1 -16.51,-7.62; 2 -13.97,-7.62; 3 -11.43,-7.62; 4 -8.89,-7.62; 5 -6.35,-7.62; 6 -3.81,-7.62; 7 -1.27,-7.62; 8 1.27,-7.62; 9 3.81,-7.62; 10 6.35,-7.62; 11 8.89,-7.62; 12 11.43,-7.62; 13 13.97,-7.62; 14 16.51,-7.62; 15 16.51,7.62; 16 13.97,7.62; 17 11.43,7.62; 18 8.89,7.62; 19 6.35,7.62; 20 3.81,7.62; 21 1.27,7.62; 22 -1.27,7.62; 23 -3.81,7.62; 24 -6.35,7.62; 25 -8.89,7.62; 26 -11.43,7.62; 27 -13.97,7.62; 28 -16.51,7.62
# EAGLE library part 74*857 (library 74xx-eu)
Hex 2-to 1 line universal MULTIPLEXER

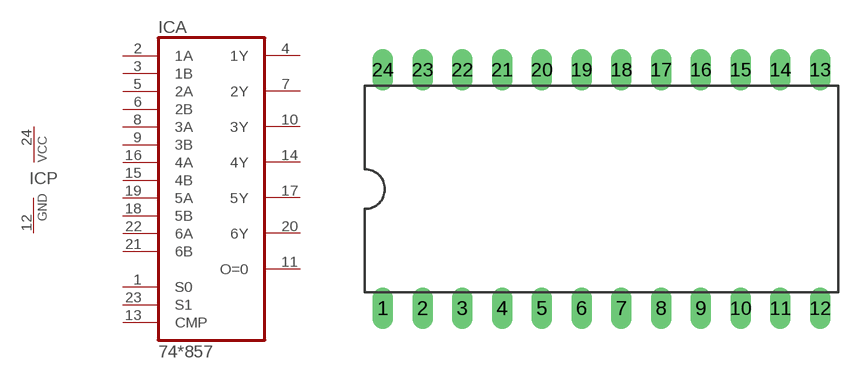
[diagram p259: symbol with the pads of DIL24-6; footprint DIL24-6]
Designator prefix IC; gates A=74857 P=PWRN

## 74ALS857NT, 74AS857NT  [DIL24-6]
1  A:S0  in
2  A:1A  in
3  A:1B  in
4  A:1Y  hiz
5  A:2A  in
6  A:2B  in
7  A:2Y  hiz
8  A:3A  in
9  A:3B  in
10  A:3Y  hiz
11  A:O=0  hiz
12  P:GND  pwr
13  A:CMP  in
14  A:4Y  hiz
15  A:4B  in
16  A:4A  in
17  A:5Y  hiz
18  A:5B  in
19  A:5A  in
20  A:6Y  hiz
21  A:6B  in
22  A:6A  in
23  A:S1  in
24  P:VCC  pwr

## Footprint DIL24-6 (pad centres in mm)
Dual In Line Package 0.6 inch
drill 0.813 long: 1 -13.97,-7.62; 2 -11.43,-7.62; 3 -8.89,-7.62; 4 -6.35,-7.62; 5 -3.81,-7.62; 6 -1.27,-7.62; 7 1.27,-7.62; 8 3.81,-7.62; 9 6.35,-7.62; 10 8.89,-7.62; 11 11.43,-7.62; 12 13.97,-7.62; 13 13.97,7.62; 14 11.43,7.62; 15 8.89,7.62; 16 6.35,7.62; 17 3.81,7.62; 18 1.27,7.62; 19 -1.27,7.62; 20 -3.81,7.62; 21 -6.35,7.62; 22 -8.89,7.62; 23 -11.43,7.62; 24 -13.97,7.62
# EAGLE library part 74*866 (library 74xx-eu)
8-bit magnitude COMPARATOR

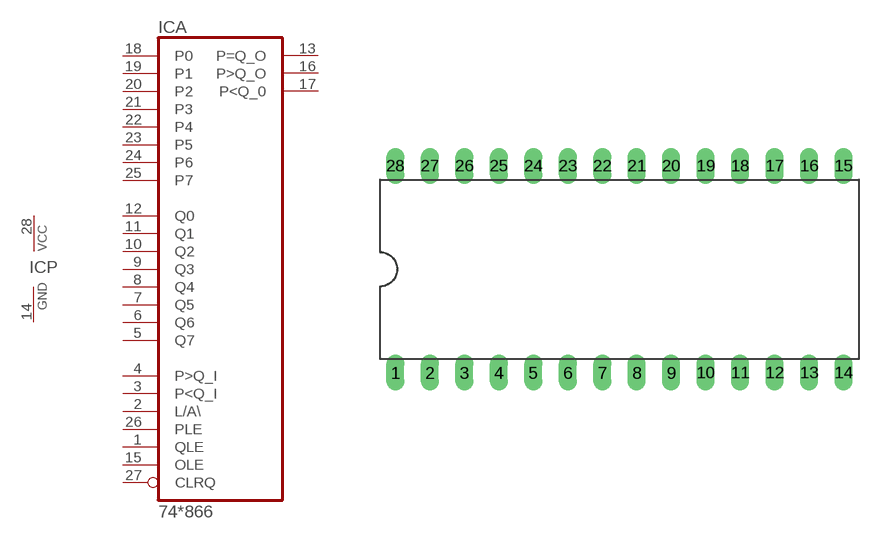
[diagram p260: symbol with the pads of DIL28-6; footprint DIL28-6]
Designator prefix IC; gates A=74866 P=PWRN

## 74AS866N  [DIL28-6]
1  A:QLE  in
2  A:L/A\  in
3  A:P<Q_I  in
4  A:P>Q_I  in
5  A:Q7  in
6  A:Q6  in
7  A:Q5  in
8  A:Q4  in
9  A:Q3  in
10  A:Q2  in
11  A:Q1  in
12  A:Q0  in
13  A:P=Q_O  oc
14  P:GND  pwr
15  A:OLE  in
16  A:P>Q_O  oc
17  A:P<Q_0  oc
18  A:P0  in
19  A:P1  in
20  A:P2  in
21  A:P3  in
22  A:P4  in
23  A:P5  in
24  A:P6  in
25  A:P7  in
26  A:PLE  in
27  A:CLRQ  in
28  P:VCC  pwr

## Footprint DIL28-6 (pad centres in mm)
Dual In Line Package 0.6 inch
drill 0.813 long: 1 -16.51,-7.62; 2 -13.97,-7.62; 3 -11.43,-7.62; 4 -8.89,-7.62; 5 -6.35,-7.62; 6 -3.81,-7.62; 7 -1.27,-7.62; 8 1.27,-7.62; 9 3.81,-7.62; 10 6.35,-7.62; 11 8.89,-7.62; 12 11.43,-7.62; 13 13.97,-7.62; 14 16.51,-7.62; 15 16.51,7.62; 16 13.97,7.62; 17 11.43,7.62; 18 8.89,7.62; 19 6.35,7.62; 20 3.81,7.62; 21 1.27,7.62; 22 -1.27,7.62; 23 -3.81,7.62; 24 -6.35,7.62; 25 -8.89,7.62; 26 -11.43,7.62; 27 -13.97,7.62; 28 -16.51,7.62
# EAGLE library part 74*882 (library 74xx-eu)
CARRY GENERATOR for 32-bit ALU

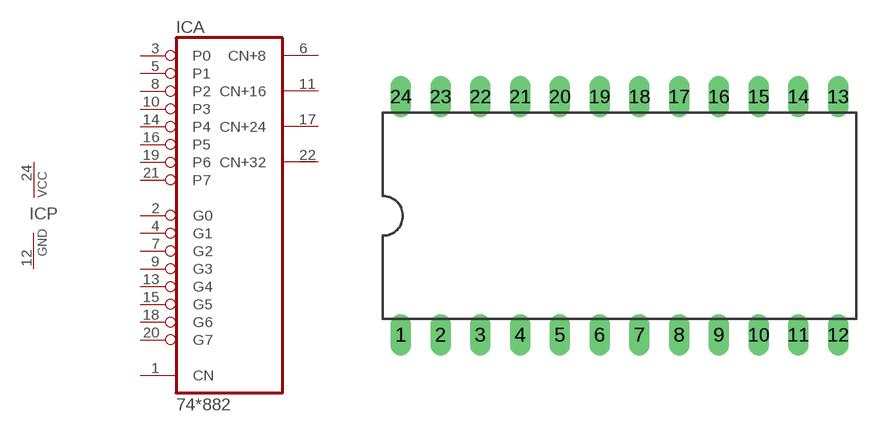
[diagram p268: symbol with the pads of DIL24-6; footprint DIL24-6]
Designator prefix IC; gates A=74882 P=PWRN

## 74AS882NT  [DIL24-6]
1  A:CN  in
2  A:G0  in
3  A:P0  in
4  A:G1  in
5  A:P1  in
6  A:CN+8  out
7  A:G2  in
8  A:P2  in
9  A:G3  in
10  A:P3  in
11  A:CN+16  out
12  P:GND  pwr
13  A:G4  in
14  A:P4  in
15  A:G5  in
16  A:P5  in
17  A:CN+24  out
18  A:G6  in
19  A:P6  in
20  A:G7  in
21  A:P7  in
22  A:CN+32  out
24  P:VCC  pwr

## Footprint DIL24-6 (pad centres in mm)
Dual In Line Package 0.6 inch
drill 0.813 long: 1 -13.97,-7.62; 2 -11.43,-7.62; 3 -8.89,-7.62; 4 -6.35,-7.62; 5 -3.81,-7.62; 6 -1.27,-7.62; 7 1.27,-7.62; 8 3.81,-7.62; 9 6.35,-7.62; 10 8.89,-7.62; 11 11.43,-7.62; 12 13.97,-7.62; 13 13.97,7.62; 14 11.43,7.62; 15 8.89,7.62; 16 6.35,7.62; 17 3.81,7.62; 18 1.27,7.62; 19 -1.27,7.62; 20 -3.81,7.62; 21 -6.35,7.62; 22 -8.89,7.62; 23 -11.43,7.62; 24 -13.97,7.62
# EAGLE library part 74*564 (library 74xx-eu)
Inverting 8-bit D type FLIP FLOP

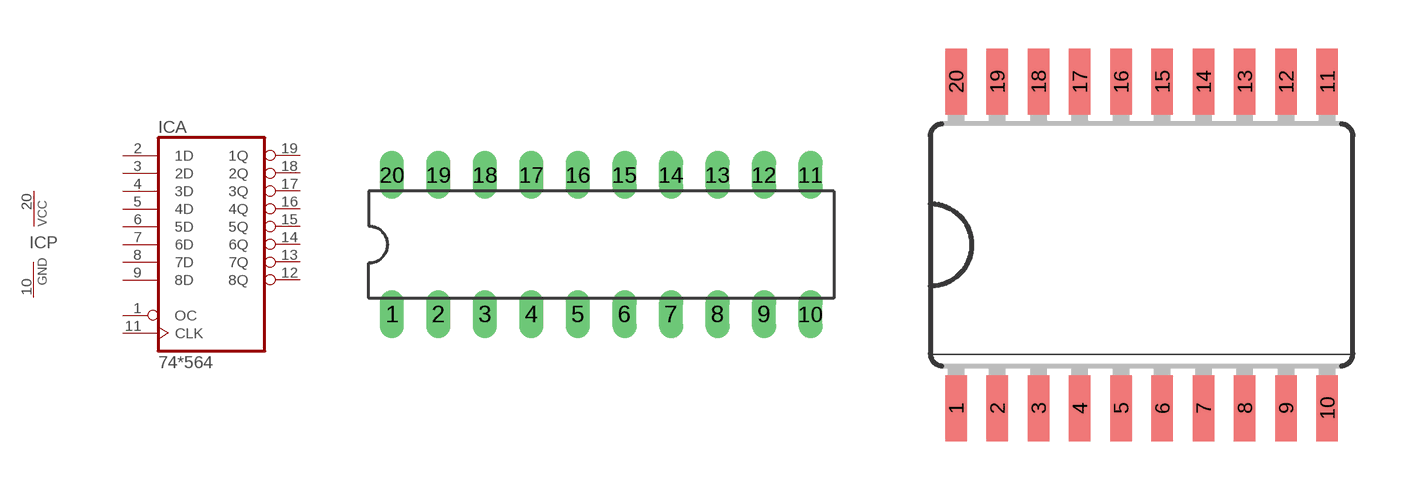
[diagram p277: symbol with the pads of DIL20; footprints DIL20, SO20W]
Designator prefix IC; gates A=74564 P=PWRN

## 74AC564N, 74ACT564N, 74ALS564N, 74HC564N, 74HCT564N  [DIL20]
1  A:OC  in
2  A:1D  in
3  A:2D  in
4  A:3D  in
5  A:4D  in
6  A:5D  in
7  A:6D  in
8  A:7D  in
9  A:8D  in
10  P:GND  pwr
11  A:CLK  in
12  A:8Q  out
13  A:7Q  out
14  A:6Q  out
15  A:5Q  out
16  A:4Q  out
17  A:3Q  out
18  A:2Q  out
19  A:1Q  out
20  P:VCC  pwr

## 74AC564D, 74ACT564D, 74HC564D, 74HCT564D  [SO20W]
Pads as for DIL20

## Footprint DIL20 (pad centres in mm)
Dual In Line Package
drill 0.813 long: 1 -11.43,-3.81; 2 -8.89,-3.81; 3 -6.35,-3.81; 4 -3.81,-3.81; 5 -1.27,-3.81; 6 1.27,-3.81; 7 3.81,-3.81; 8 6.35,-3.81; 9 8.89,-3.81; 10 11.43,-3.81; 11 11.43,3.81; 12 8.89,3.81; 13 6.35,3.81; 14 3.81,3.81; 15 1.27,3.81; 16 -1.27,3.81; 17 -3.81,3.81; 18 -6.35,3.81; 19 -8.89,3.81; 20 -11.43,3.81

## Footprint SO20W (pad centres in mm)
Wide Small Outline package 300 mil
smd 0.66 x 2.032: 1 -5.715,-5.029; 2 -4.445,-5.029; 3 -3.175,-5.029; 4 -1.905,-5.029; 5 -0.635,-5.029; 6 0.635,-5.029; 7 1.905,-5.029; 8 3.175,-5.029; 9 4.445,-5.029; 10 5.715,-5.029; 11 5.715,5.029; 12 4.445,5.029; 13 3.175,5.029; 14 1.905,5.029; 15 0.635,5.029; 16 -0.635,5.029; 17 -1.905,5.029; 18 -3.175,5.029; 19 -4.445,5.029; 20 -5.715,5.029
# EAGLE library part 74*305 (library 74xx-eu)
Octal devide by 2 CIRCUITS/CLOCK DRIVER

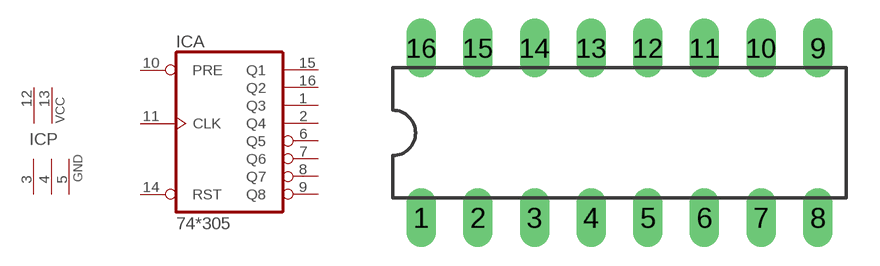
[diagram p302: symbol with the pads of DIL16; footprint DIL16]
Designator prefix IC; gates P=2PWR3GND A=74305

## 74305N  [DIL16]
1  A:Q3  out
2  A:Q4  out
3  P:GND  pwr
4  P:GND  pwr
5  P:GND  pwr
6  A:Q5  out
7  A:Q6  out
8  A:Q7  out
9  A:Q8  out
10  A:PRE  in
11  A:CLK  in
12  P:VCC  pwr
13  P:VCC  pwr
14  A:RST  in
15  A:Q1  out
16  A:Q2  out

## Footprint DIL16 (pad centres in mm)
Dual In Line Package
drill 0.813 long: 1 -8.89,-3.81; 2 -6.35,-3.81; 3 -3.81,-3.81; 4 -1.27,-3.81; 5 1.27,-3.81; 6 3.81,-3.81; 7 6.35,-3.81; 8 8.89,-3.81; 9 8.89,3.81; 10 6.35,3.81; 11 3.81,3.81; 12 1.27,3.81; 13 -1.27,3.81; 14 -3.81,3.81; 15 -6.35,3.81; 16 -8.89,3.81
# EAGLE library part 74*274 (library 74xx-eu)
4 by 4-bit MULTIPLIER

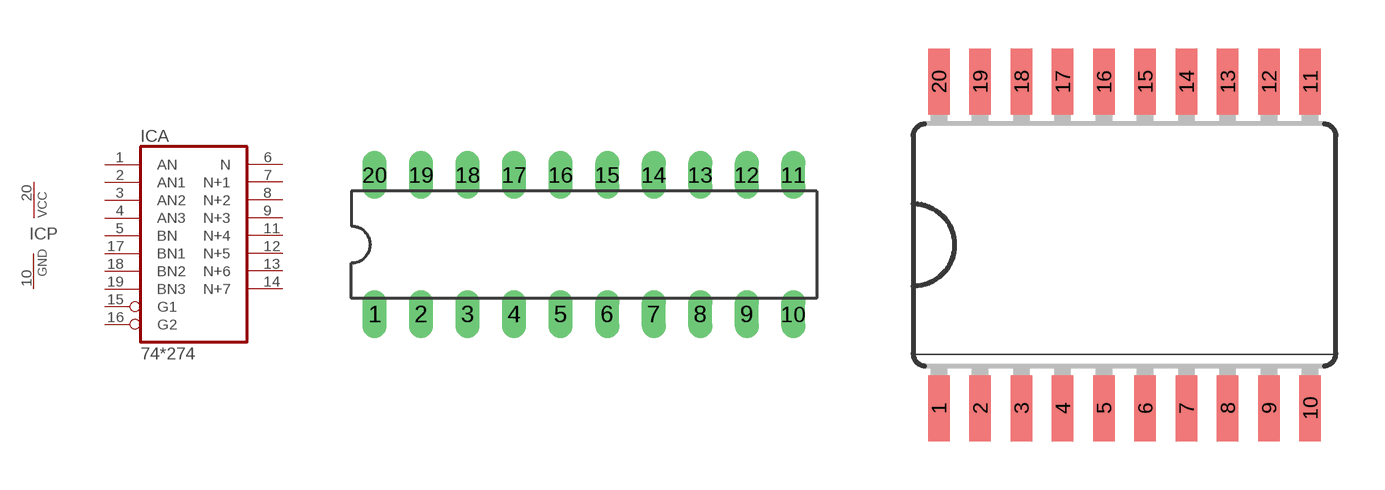
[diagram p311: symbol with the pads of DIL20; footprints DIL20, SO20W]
Designator prefix IC; gates A=74274 P=PWRN

## 74AC274N, 74ACT274N, 74HC274N, 74HCT274N, 74S274N  [DIL20]
1  A:AN  in
2  A:AN1  in
3  A:AN2  in
4  A:AN3  in
5  A:BN  in
6  A:N  out
7  A:N+1  out
8  A:N+2  out
9  A:N+3  out
10  P:GND  pwr
11  A:N+4  out
12  A:N+5  out
13  A:N+6  out
14  A:N+7  out
15  A:G1  in
16  A:G2  in
17  A:BN1  in
18  A:BN2  in
19  A:BN3  in
20  P:VCC  pwr

## 74274J, 74AC274J, 74ACT274J, 74HC274J, 74HCT274J  [SO20W]
Pads as for DIL20

## Footprint DIL20 (pad centres in mm)
Dual In Line Package
drill 0.813 long: 1 -11.43,-3.81; 2 -8.89,-3.81; 3 -6.35,-3.81; 4 -3.81,-3.81; 5 -1.27,-3.81; 6 1.27,-3.81; 7 3.81,-3.81; 8 6.35,-3.81; 9 8.89,-3.81; 10 11.43,-3.81; 11 11.43,3.81; 12 8.89,3.81; 13 6.35,3.81; 14 3.81,3.81; 15 1.27,3.81; 16 -1.27,3.81; 17 -3.81,3.81; 18 -6.35,3.81; 19 -8.89,3.81; 20 -11.43,3.81

## Footprint SO20W (pad centres in mm)
Wide Small Outline package 300 mil
smd 0.66 x 2.032: 1 -5.715,-5.029; 2 -4.445,-5.029; 3 -3.175,-5.029; 4 -1.905,-5.029; 5 -0.635,-5.029; 6 0.635,-5.029; 7 1.905,-5.029; 8 3.175,-5.029; 9 4.445,-5.029; 10 5.715,-5.029; 11 5.715,5.029; 12 4.445,5.029; 13 3.175,5.029; 14 1.905,5.029; 15 0.635,5.029; 16 -0.635,5.029; 17 -1.905,5.029; 18 -3.175,5.029; 19 -4.445,5.029; 20 -5.715,5.029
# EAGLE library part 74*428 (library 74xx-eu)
SYSTEM CONTROLLER/BUS DRIVER for 8080 (=Intel 8228)

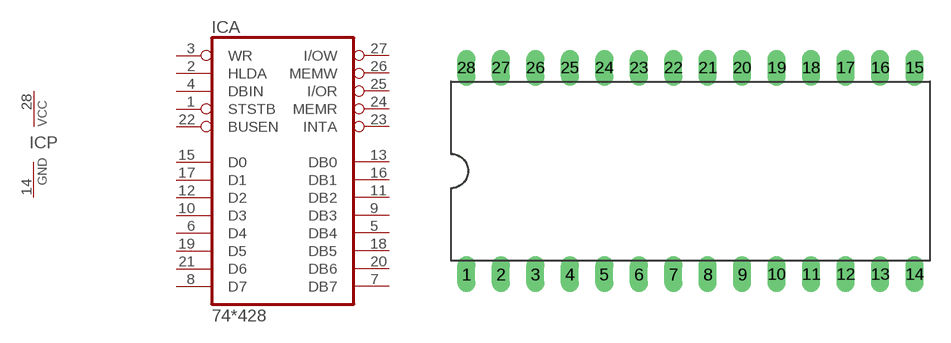
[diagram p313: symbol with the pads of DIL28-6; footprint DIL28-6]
Designator prefix IC; gates P=PWRN A=74428

## 74428N  [DIL28-6]
1  A:STSTB  in
2  A:HLDA  in
3  A:WR  in
4  A:DBIN  in
5  A:DB4
6  A:D4
7  A:DB7
8  A:D7
9  A:DB3
10  A:D3
11  A:DB2
12  A:D2
13  A:DB0
14  P:GND  pwr
15  A:D0
16  A:DB1
17  A:D1
18  A:DB5
19  A:D5
20  A:DB6
21  A:D6
22  A:BUSEN  in
23  A:INTA  out
24  A:MEMR  out
25  A:I/OR  out
26  A:MEMW  out
27  A:I/OW  out
28  P:VCC  pwr

## Footprint DIL28-6 (pad centres in mm)
Dual In Line Package 0.6 inch
drill 0.813 long: 1 -16.51,-7.62; 2 -13.97,-7.62; 3 -11.43,-7.62; 4 -8.89,-7.62; 5 -6.35,-7.62; 6 -3.81,-7.62; 7 -1.27,-7.62; 8 1.27,-7.62; 9 3.81,-7.62; 10 6.35,-7.62; 11 8.89,-7.62; 12 11.43,-7.62; 13 13.97,-7.62; 14 16.51,-7.62; 15 16.51,7.62; 16 13.97,7.62; 17 11.43,7.62; 18 8.89,7.62; 19 6.35,7.62; 20 3.81,7.62; 21 1.27,7.62; 22 -1.27,7.62; 23 -3.81,7.62; 24 -6.35,7.62; 25 -8.89,7.62; 26 -11.43,7.62; 27 -13.97,7.62; 28 -16.51,7.62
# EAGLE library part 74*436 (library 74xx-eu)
Hex inverting LINE DRIVER

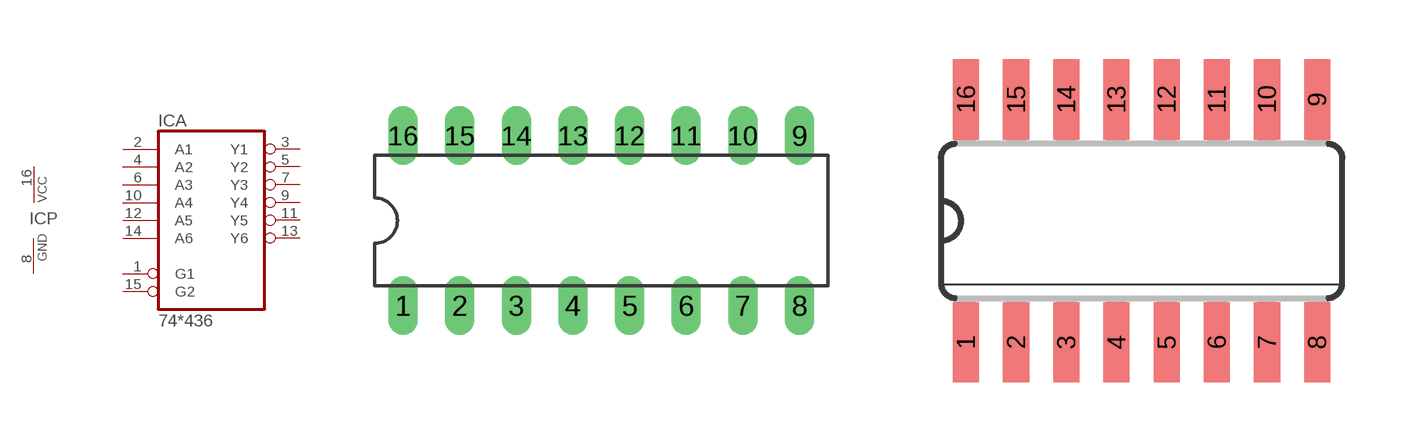
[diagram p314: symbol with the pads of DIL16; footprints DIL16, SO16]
Designator prefix IC; gates A=74436 P=PWRN

## 74S436N  [DIL16]
1  A:G1  in
2  A:A1  in
3  A:Y1  out
4  A:A2  in
5  A:Y2  out
6  A:A3  in
7  A:Y3  out
8  P:GND  pwr
9  A:Y4  out
10  A:A4  in
11  A:Y5  out
12  A:A5  in
13  A:Y6  out
14  A:A6  in
15  A:G2  in
16  P:VCC  pwr

## 74S436J  [SO16]
Pads as for DIL16

## Footprint DIL16 (pad centres in mm)
Dual In Line Package
drill 0.813 long: 1 -8.89,-3.81; 2 -6.35,-3.81; 3 -3.81,-3.81; 4 -1.27,-3.81; 5 1.27,-3.81; 6 3.81,-3.81; 7 6.35,-3.81; 8 8.89,-3.81; 9 8.89,3.81; 10 6.35,3.81; 11 3.81,3.81; 12 1.27,3.81; 13 -1.27,3.81; 14 -3.81,3.81; 15 -6.35,3.81; 16 -8.89,3.81

## Footprint SO16 (pad centres in mm)
Small Outline package 150 mil
smd 0.66 x 2.032: 1 -4.445,-3.073; 2 -3.175,-3.073; 3 -1.905,-3.073; 4 -0.635,-3.073; 5 0.635,-3.073; 6 1.905,-3.073; 7 3.175,-3.073; 8 4.445,-3.073; 9 4.445,3.073; 10 3.175,3.073; 11 1.905,3.073; 12 0.635,3.073; 13 -0.635,3.073; 14 -1.905,3.073; 15 -3.175,3.073; 16 -4.445,3.073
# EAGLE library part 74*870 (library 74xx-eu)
2 x 16 REGISTER, 4 bit each

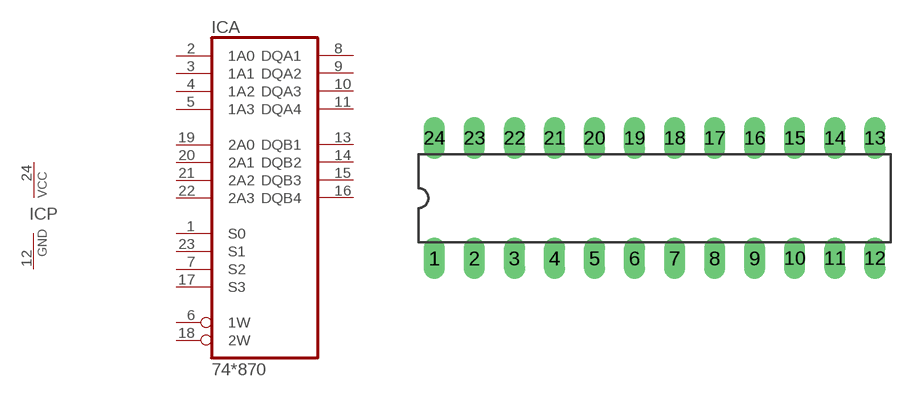
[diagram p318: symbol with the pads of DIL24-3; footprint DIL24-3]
Designator prefix IC; gates A=74870 P=PWRN

## 74AS870NT  [DIL24-3]
1  A:S0  in
2  A:1A0  in
3  A:1A1  in
4  A:1A2  in
5  A:1A3  in
6  A:1W  in
7  A:S2  in
8  A:DQA1
9  A:DQA2
10  A:DQA3
11  A:DQA4
12  P:GND  pwr
13  A:DQB1
14  A:DQB2
15  A:DQB3
16  A:DQB4
17  A:S3  in
18  A:2W  in
19  A:2A0  in
20  A:2A1  in
21  A:2A2  in
22  A:2A3  in
23  A:S1  in
24  P:VCC  pwr

## Footprint DIL24-3 (pad centres in mm)
Dual In Line Package 0.3 inch
drill 0.813 long: 1 -13.97,-3.81; 2 -11.43,-3.81; 3 -8.89,-3.81; 4 -6.35,-3.81; 5 -3.81,-3.81; 6 -1.27,-3.81; 7 1.27,-3.81; 8 3.81,-3.81; 9 6.35,-3.81; 10 8.89,-3.81; 11 11.43,-3.81; 12 13.97,-3.81; 13 13.97,3.81; 14 11.43,3.81; 15 8.89,3.81; 16 6.35,3.81; 17 3.81,3.81; 18 1.27,3.81; 19 -1.27,3.81; 20 -3.81,3.81; 21 -6.35,3.81; 22 -8.89,3.81; 23 -11.43,3.81; 24 -13.97,3.81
